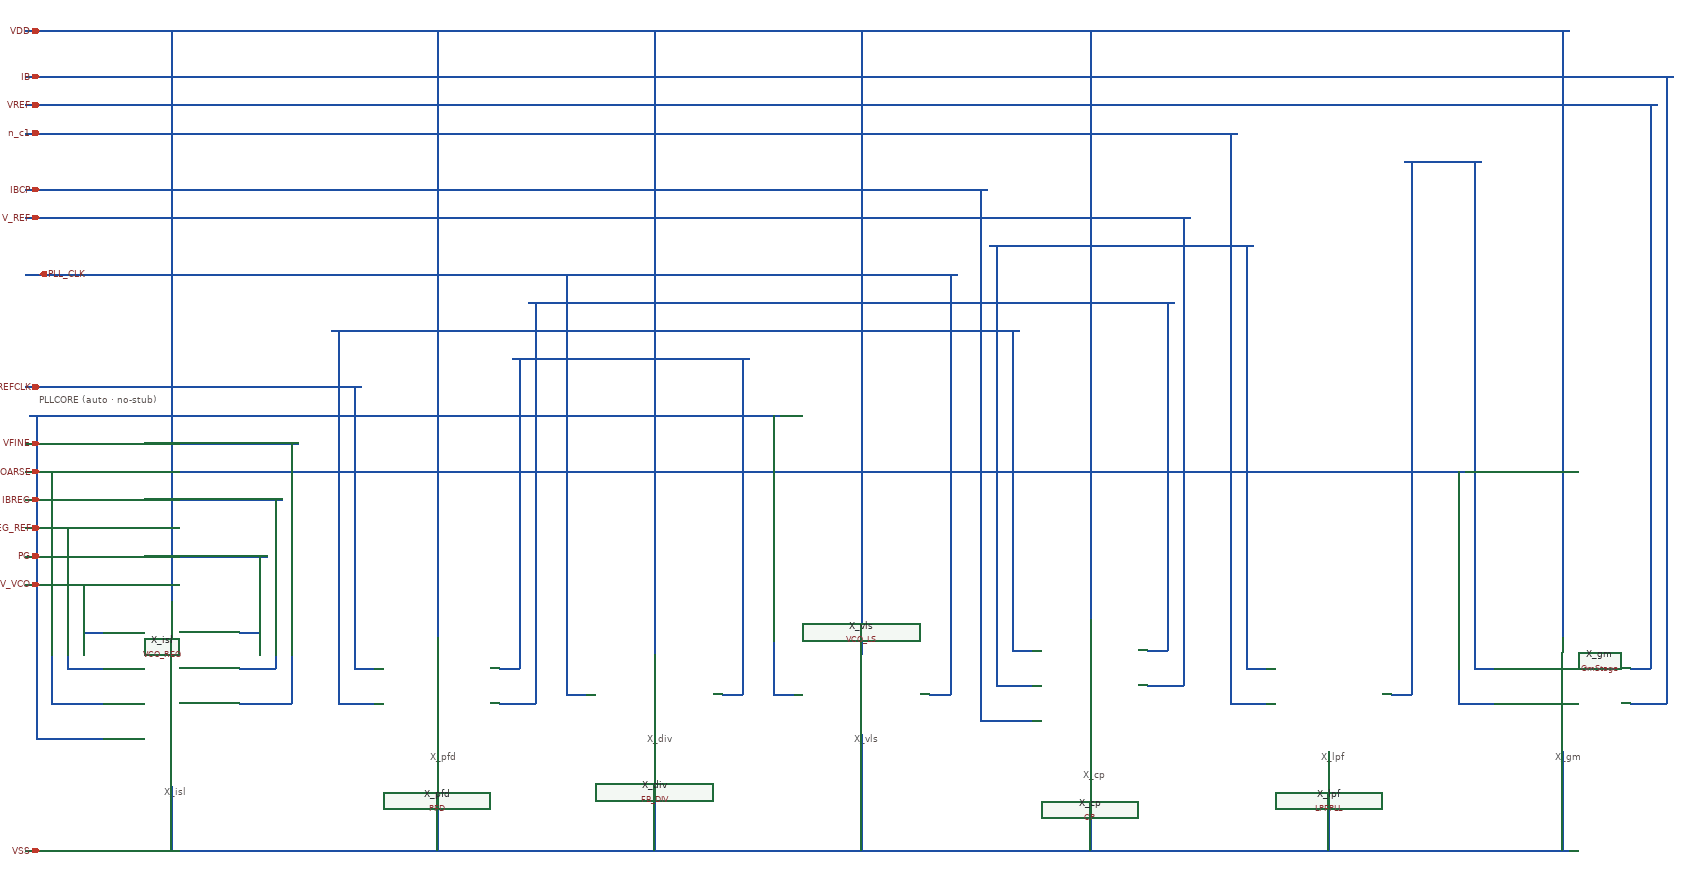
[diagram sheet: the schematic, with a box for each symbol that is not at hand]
v {xschem version=3.4.6 file_version=1.2}
G {}
K {}
V {}
S {}
E {}
T {PLLCORE   (auto · no-stub)} -300 -680 0 0 0.4 0.4 {layer=4}
C {VCO_REG.sym} 0 0 0 0 {name=X_isl}
N 0 -210 0 -256 {}
N 0 210 0 256 {}
N -154 -140 -200 -140 {}
N 154 -140 200 -140 {}
N -154 -60 -236 -60 {}
N 154 -60 236 -60 {}
N -154 20 -272 20 {}
N 154 20 272 20 {}
N -154 100 -308 100 {}
T {X_isl} -16 210 0 0 0.11 0.11 {layer=13}
C {PFD.sym} 602 0 0 0 {name=X_pfd}
N 460 -60 414 -60 {}
N 744 -60 790 -60 {}
N 460 20 378 20 {}
N 744 20 826 20 {}
N 602 -130 602 -176 {}
N 602 130 602 176 {}
T {X_pfd} 586 130 0 0 0.11 0.11 {layer=13}
C {FB_DIV.sym} 1096 0 0 0 {name=X_div}
N 1096 -90 1096 -136 {}
N 1096 90 1096 136 {}
N 942 0 896 0 {}
N 1250 0 1296 0 {}
T {X_div} 1080 90 0 0 0.11 0.11 {layer=13}
C {VCO_LS.sym} 1566 0 0 0 {name=X_vls}
N 1566 -90 1566 -136 {}
N 1566 90 1566 136 {}
N 1412 0 1366 0 {}
N 1720 0 1766 0 {}
T {X_vls} 1550 90 0 0 0.11 0.11 {layer=13}
C {CP.sym} 2084 0 0 0 {name=X_cp}
N 1954 -100 1908 -100 {}
N 2214 -100 2260 -100 {}
N 1954 -20 1872 -20 {}
N 2214 -20 2296 -20 {}
N 2084 -170 2084 -216 {}
N 1954 60 1836 60 {}
N 2084 170 2084 216 {}
T {X_cp} 2068 170 0 0 0.11 0.11 {layer=13}
C {LPFPLL.sym} 2626 0 0 0 {name=X_lpf}
N 2626 130 2626 176 {}
N 2484 -60 2438 -60 {}
N 2768 0 2814 0 {}
N 2484 20 2402 20 {}
T {X_lpf} 2610 130 0 0 0.11 0.11 {layer=13}
C {GmStage.sym} 3156 0 0 0 {name=X_gm}
N 3156 -130 3156 -176 {}
N 3156 130 3156 176 {}
N 3002 -60 2956 -60 {}
N 3310 -60 3356 -60 {}
N 3002 20 2920 20 {}
N 3310 20 3392 20 {}
T {X_gm} 3140 130 0 0 0.11 0.11 {layer=13}
N 0 -256 0 -1506 {}
N 602 -176 602 -1506 {}
N 1096 -136 1096 -1506 {}
N 1566 -136 1566 -1506 {}
N 2084 -216 2084 -1506 {}
N 3156 -176 3156 -1506 {}
N 0 256 0 354 {}
N 602 176 602 354 {}
N 1096 136 1096 354 {}
N 1566 136 1566 354 {}
N 2084 216 2084 354 {}
N 2626 176 2626 354 {}
N 3156 176 3156 354 {}
N -200 -140 -200 -250 {}
N 200 -140 200 -314 {}
N -236 -60 -236 -378 {}
N 236 -60 236 -442 {}
N -272 20 -272 -506 {}
N 2920 20 2920 -506 {}
N 272 20 272 -570 {}
N -308 100 -308 -634 {}
N 1366 0 1366 -634 {}
N 414 -60 414 -698 {}
N 790 -60 790 -762 {}
N 1296 0 1296 -762 {}
N 378 20 378 -826 {}
N 1908 -100 1908 -826 {}
N 826 20 826 -890 {}
N 2260 -100 2260 -890 {}
N 896 0 896 -954 {}
N 1766 0 1766 -954 {}
N 1872 -20 1872 -1018 {}
N 2438 -60 2438 -1018 {}
N 2296 -20 2296 -1082 {}
N 1836 60 1836 -1146 {}
N 2814 0 2814 -1210 {}
N 2956 -60 2956 -1210 {}
N 2402 20 2402 -1274 {}
N 3356 -60 3356 -1338 {}
N 3392 20 3392 -1402 {}
C {devices/ipin.sym} -300 -1506 0 0 {name=ip1 lab=VDD}
C {devices/ipin.sym} -300 354 0 0 {name=ip2 lab=VSS}
C {devices/ipin.sym} -300 -570 0 0 {name=ip3 lab=VFINE}
C {devices/ipin.sym} -300 -698 0 0 {name=ip4 lab=REFCLK}
C {devices/ipin.sym} -300 -1082 0 0 {name=ip5 lab=V_REF}
C {devices/ipin.sym} -300 -378 0 0 {name=ip6 lab=VREG_REF}
C {devices/ipin.sym} -300 -1146 0 0 {name=ip7 lab=IBCP}
C {devices/ipin.sym} -300 -442 0 0 {name=ip8 lab=IBREG}
C {devices/ipin.sym} -300 -314 0 0 {name=ip9 lab=PG}
C {devices/ipin.sym} -300 -1338 0 0 {name=ip10 lab=VREF}
C {devices/ipin.sym} -300 -1402 0 0 {name=ip11 lab=IB}
C {devices/ipin.sym} -300 -506 0 0 {name=ip12 lab=VCOARSE}
C {devices/ipin.sym} -300 -250 0 0 {name=ip13 lab=V_VCO}
C {devices/ipin.sym} -300 -1274 0 0 {name=ip14 lab=n_c1}
C {devices/opin.sym} -300 -954 0 0 {name=op15 lab=PLL_CLK}
N -332 -1506 3172 -1506 {lab=VDD}
N -332 354 3172 354 {lab=VSS}
N -332 -250 -184 -250 {}
N -332 -314 216 -314 {}
N -332 -378 -220 -378 {}
N -332 -442 252 -442 {}
N -332 -506 2936 -506 {}
N -332 -570 288 -570 {}
N -324 -634 1382 -634 {}
N -332 -698 430 -698 {}
N 774 -762 1312 -762 {}
N 362 -826 1924 -826 {}
N 810 -890 2276 -890 {}
N -332 -954 1782 -954 {}
N 1856 -1018 2454 -1018 {}
N -332 -1082 2312 -1082 {}
N -332 -1146 1852 -1146 {}
N 2798 -1210 2972 -1210 {}
N -332 -1274 2418 -1274 {}
N -332 -1338 3372 -1338 {}
N -332 -1402 3408 -1402 {}
